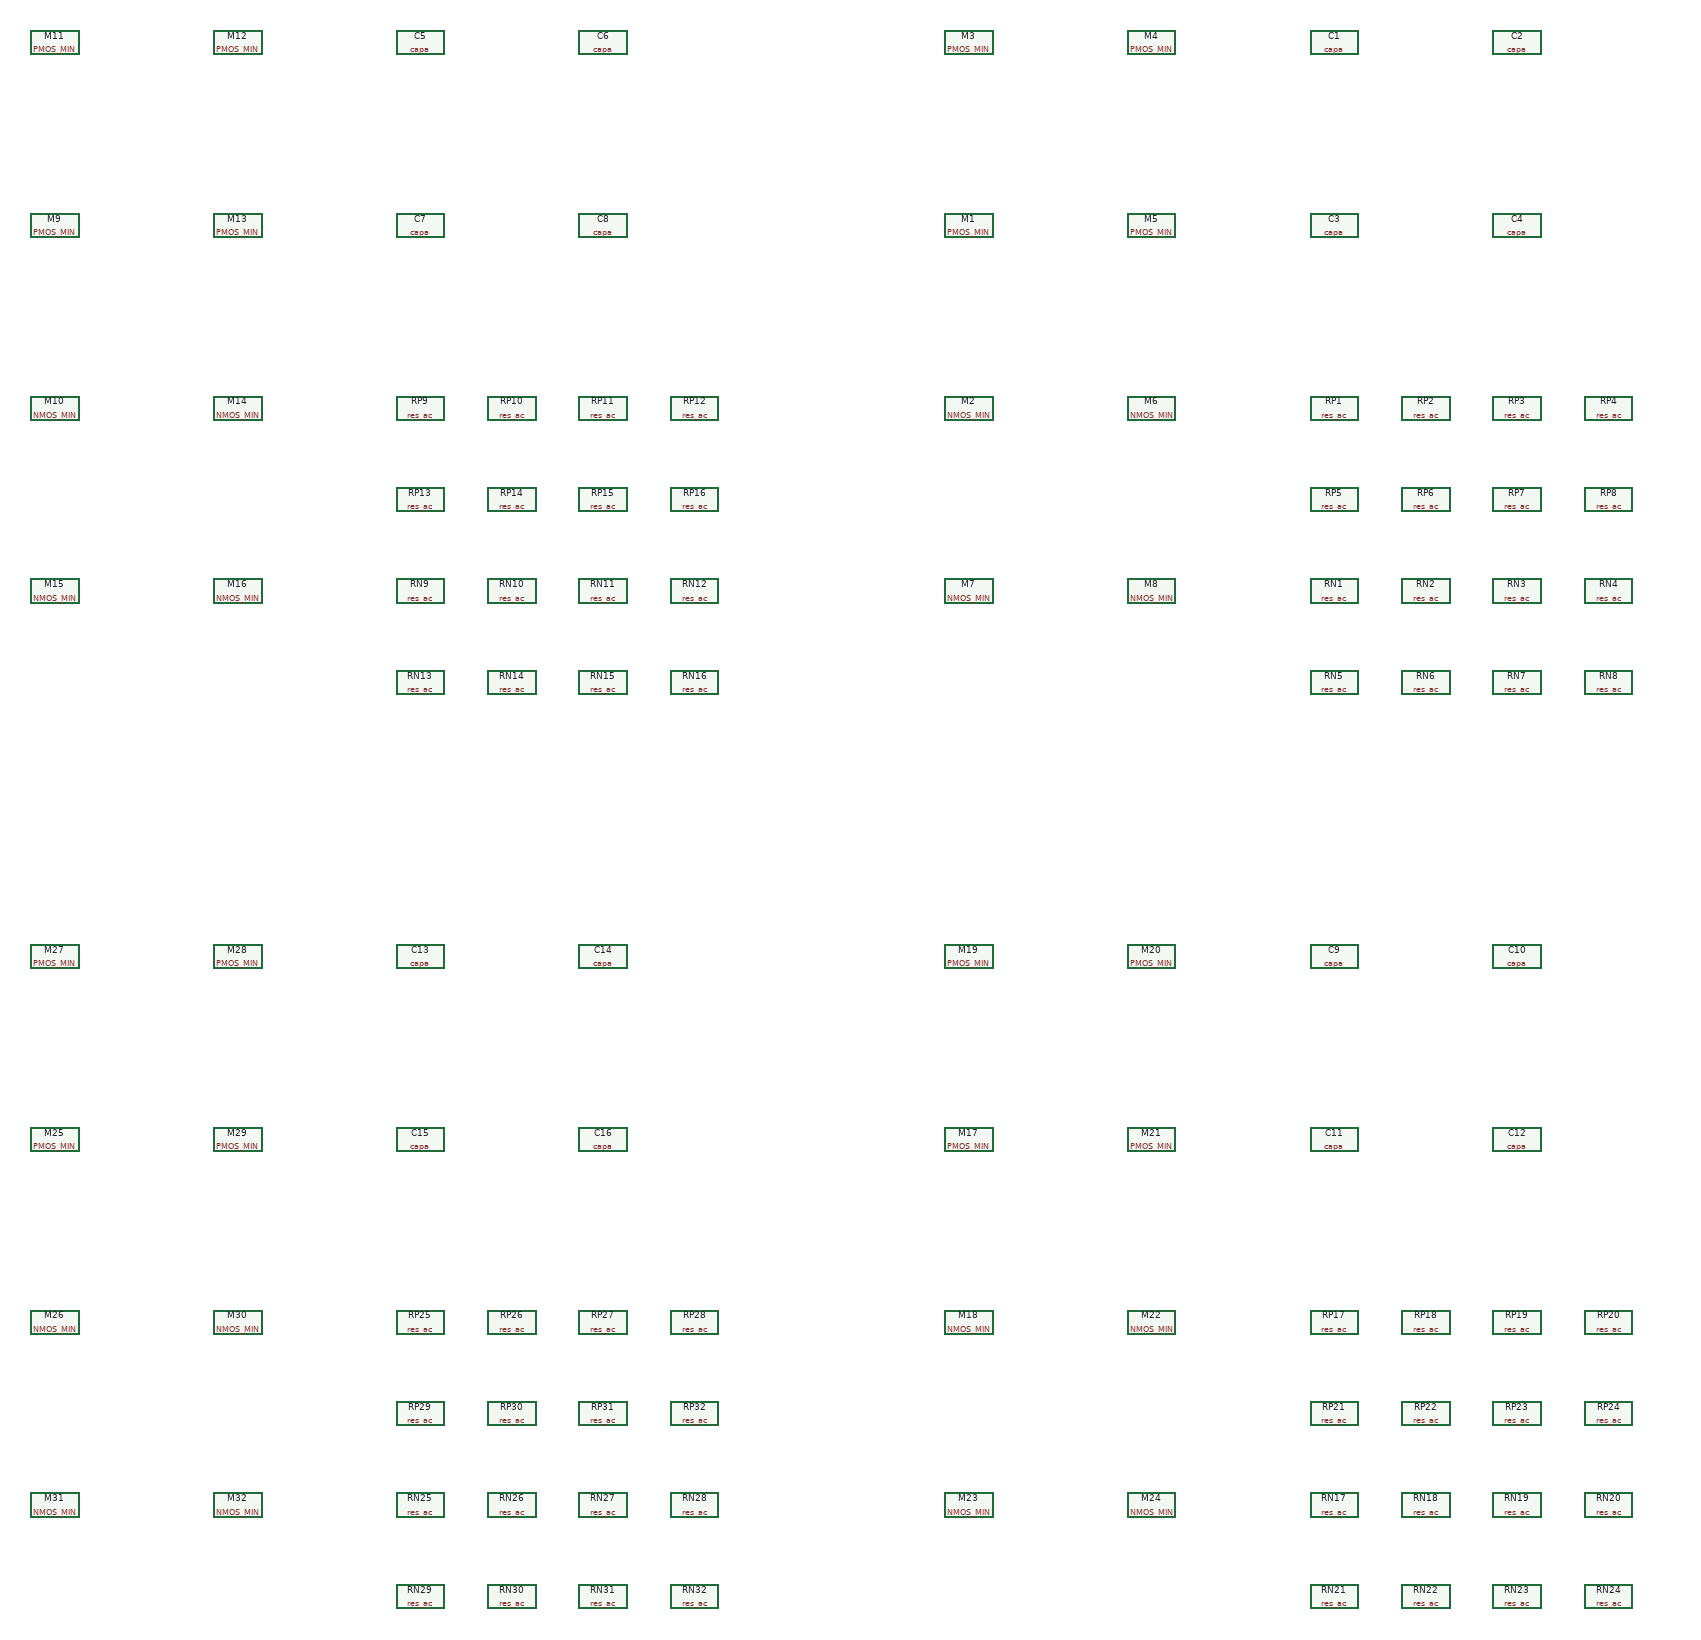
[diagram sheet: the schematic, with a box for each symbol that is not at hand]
v {xschem version=3.4.6RC file_version=1.2
}
G {}
K {}
V {}
S {}
E {}
C {PMOS_MIN.sym} 300 -900 0 0 {name=M1 model=pch w=40u l=10u as=0 ps=0 ad=0 pd=0 m=1}
C {NMOS_MIN.sym} 300 -600 0 0 {name=M2 model=nch w=10u l=10u as=0 ps=0 ad=0 pd=0 m=1}
C {PMOS_MIN.sym} 300 -1200 0 0 {name=M3 model=pch w=40u l=10u as=0 ps=0 ad=0 pd=0 m=1}
C {PMOS_MIN.sym} 600 -1200 0 0 {name=M4 model=pch w=40u l=10u as=0 ps=0 ad=0 pd=0 m=1}
C {PMOS_MIN.sym} 600 -900 0 0 {name=M5 model=pch w=40u l=10u as=0 ps=0 ad=0 pd=0 m=1}
C {NMOS_MIN.sym} 600 -600 0 0 {name=M6 model=nch w=10u l=10u as=0 ps=0 ad=0 pd=0 m=1}
C {NMOS_MIN.sym} 300 -300 0 0 {name=M7 model=nch w=10u l=10u as=0 ps=0 ad=0 pd=0 m=1}
C {NMOS_MIN.sym} 600 -300 0 0 {name=M8 model=nch w=10u l=10u as=0 ps=0 ad=0 pd=0 m=1}
C {devices/capa.sym} 900 -1200 0 0 {name=C1
m=1
value=0.413p
footprint=1206
device="ceramic capacitor"}
C {devices/capa.sym} 1200 -1200 0 0 {name=C2
m=1
value=0.413p
footprint=1206
device="ceramic capacitor"}
C {devices/capa.sym} 900 -900 0 0 {name=C3
m=1
value=0.413p
footprint=1206
device="ceramic capacitor"}
C {devices/capa.sym} 1200 -900 0 0 {name=C4
m=1
value=0.413p
footprint=1206
device="ceramic capacitor"}
C {devices/res_ac.sym} 900 -600 0 0 {name=RP1
value=3.6k
ac=1k
m=1}
C {devices/res_ac.sym} 1050 -600 0 0 {name=RP2
value=3.6k
ac=1k
m=1}
C {devices/res_ac.sym} 1200 -600 0 0 {name=RP3
value=3.6k
ac=1k
m=1}
C {devices/res_ac.sym} 1350 -600 0 0 {name=RP4
value=3.6k
ac=1k
m=1}
C {devices/res_ac.sym} 900 -450 0 0 {name=RP5
value=3.6k
ac=1k
m=1}
C {devices/res_ac.sym} 1050 -450 0 0 {name=RP6
value=3.6k
ac=1k
m=1}
C {devices/res_ac.sym} 1200 -450 0 0 {name=RP7
value=3.6k
ac=1k
m=1}
C {devices/res_ac.sym} 1350 -450 0 0 {name=RP8
value=3.6k
ac=1k
m=1}
C {devices/res_ac.sym} 900 -300 0 0 {name=RN1
value=0.54k
ac=1k
m=1}
C {devices/res_ac.sym} 1050 -300 0 0 {name=RN2
value=0.54k
ac=1k
m=1}
C {devices/res_ac.sym} 1200 -300 0 0 {name=RN3
value=0.54k
ac=1k
m=1}
C {devices/res_ac.sym} 1350 -300 0 0 {name=RN4
value=0.54k
ac=1k
m=1}
C {devices/res_ac.sym} 900 -150 0 0 {name=RN5
value=0.54k
ac=1k
m=1}
C {devices/res_ac.sym} 1050 -150 0 0 {name=RN6
value=0.54k
ac=1k
m=1}
C {devices/res_ac.sym} 1200 -150 0 0 {name=RN7
value=0.54k
ac=1k
m=1}
C {devices/res_ac.sym} 1350 -150 0 0 {name=RN8
value=0.54k
ac=1k
m=1}
C {PMOS_MIN.sym} -1200 -900 0 0 {name=M9 model=pch w=40u l=10u as=0 ps=0 ad=0 pd=0 m=1}
C {NMOS_MIN.sym} -1200 -600 0 0 {name=M10 model=nch w=10u l=10u as=0 ps=0 ad=0 pd=0 m=1}
C {PMOS_MIN.sym} -1200 -1200 0 0 {name=M11 model=pch w=40u l=10u as=0 ps=0 ad=0 pd=0 m=1}
C {PMOS_MIN.sym} -900 -1200 0 0 {name=M12 model=pch w=40u l=10u as=0 ps=0 ad=0 pd=0 m=1}
C {PMOS_MIN.sym} -900 -900 0 0 {name=M13 model=pch w=40u l=10u as=0 ps=0 ad=0 pd=0 m=1}
C {NMOS_MIN.sym} -900 -600 0 0 {name=M14 model=nch w=10u l=10u as=0 ps=0 ad=0 pd=0 m=1}
C {NMOS_MIN.sym} -1200 -300 0 0 {name=M15 model=nch w=10u l=10u as=0 ps=0 ad=0 pd=0 m=1}
C {NMOS_MIN.sym} -900 -300 0 0 {name=M16 model=nch w=10u l=10u as=0 ps=0 ad=0 pd=0 m=1}
C {devices/capa.sym} -600 -1200 0 0 {name=C5
m=1
value=0.413p
footprint=1206
device="ceramic capacitor"}
C {devices/capa.sym} -300 -1200 0 0 {name=C6
m=1
value=0.413p
footprint=1206
device="ceramic capacitor"}
C {devices/capa.sym} -600 -900 0 0 {name=C7
m=1
value=0.413p
footprint=1206
device="ceramic capacitor"}
C {devices/capa.sym} -300 -900 0 0 {name=C8
m=1
value=0.413p
footprint=1206
device="ceramic capacitor"}
C {devices/res_ac.sym} -600 -600 0 0 {name=RP9
value=3.6k
ac=1k
m=1}
C {devices/res_ac.sym} -450 -600 0 0 {name=RP10
value=3.6k
ac=1k
m=1}
C {devices/res_ac.sym} -300 -600 0 0 {name=RP11
value=3.6k
ac=1k
m=1}
C {devices/res_ac.sym} -150 -600 0 0 {name=RP12
value=3.6k
ac=1k
m=1}
C {devices/res_ac.sym} -600 -450 0 0 {name=RP13
value=3.6k
ac=1k
m=1}
C {devices/res_ac.sym} -450 -450 0 0 {name=RP14
value=3.6k
ac=1k
m=1}
C {devices/res_ac.sym} -300 -450 0 0 {name=RP15
value=3.6k
ac=1k
m=1}
C {devices/res_ac.sym} -150 -450 0 0 {name=RP16
value=3.6k
ac=1k
m=1}
C {devices/res_ac.sym} -600 -300 0 0 {name=RN9
value=0.54k
ac=1k
m=1}
C {devices/res_ac.sym} -450 -300 0 0 {name=RN10
value=0.54k
ac=1k
m=1}
C {devices/res_ac.sym} -300 -300 0 0 {name=RN11
value=0.54k
ac=1k
m=1}
C {devices/res_ac.sym} -150 -300 0 0 {name=RN12
value=0.54k
ac=1k
m=1}
C {devices/res_ac.sym} -600 -150 0 0 {name=RN13
value=0.54k
ac=1k
m=1}
C {devices/res_ac.sym} -450 -150 0 0 {name=RN14
value=0.54k
ac=1k
m=1}
C {devices/res_ac.sym} -300 -150 0 0 {name=RN15
value=0.54k
ac=1k
m=1}
C {devices/res_ac.sym} -150 -150 0 0 {name=RN16
value=0.54k
ac=1k
m=1}
C {PMOS_MIN.sym} 300 600 0 0 {name=M17 model=pch w=40u l=10u as=0 ps=0 ad=0 pd=0 m=1}
C {NMOS_MIN.sym} 300 900 0 0 {name=M18 model=nch w=10u l=10u as=0 ps=0 ad=0 pd=0 m=1}
C {PMOS_MIN.sym} 300 300 0 0 {name=M19 model=pch w=40u l=10u as=0 ps=0 ad=0 pd=0 m=1}
C {PMOS_MIN.sym} 600 300 0 0 {name=M20 model=pch w=40u l=10u as=0 ps=0 ad=0 pd=0 m=1}
C {PMOS_MIN.sym} 600 600 0 0 {name=M21 model=pch w=40u l=10u as=0 ps=0 ad=0 pd=0 m=1}
C {NMOS_MIN.sym} 600 900 0 0 {name=M22 model=nch w=10u l=10u as=0 ps=0 ad=0 pd=0 m=1}
C {NMOS_MIN.sym} 300 1200 0 0 {name=M23 model=nch w=10u l=10u as=0 ps=0 ad=0 pd=0 m=1}
C {NMOS_MIN.sym} 600 1200 0 0 {name=M24 model=nch w=10u l=10u as=0 ps=0 ad=0 pd=0 m=1}
C {devices/capa.sym} 900 300 0 0 {name=C9
m=1
value=0.413p
footprint=1206
device="ceramic capacitor"}
C {devices/capa.sym} 1200 300 0 0 {name=C10
m=1
value=0.413p
footprint=1206
device="ceramic capacitor"}
C {devices/capa.sym} 900 600 0 0 {name=C11
m=1
value=0.413p
footprint=1206
device="ceramic capacitor"}
C {devices/capa.sym} 1200 600 0 0 {name=C12
m=1
value=0.413p
footprint=1206
device="ceramic capacitor"}
C {devices/res_ac.sym} 900 900 0 0 {name=RP17
value=3.6k
ac=1k
m=1}
C {devices/res_ac.sym} 1050 900 0 0 {name=RP18
value=3.6k
ac=1k
m=1}
C {devices/res_ac.sym} 1200 900 0 0 {name=RP19
value=3.6k
ac=1k
m=1}
C {devices/res_ac.sym} 1350 900 0 0 {name=RP20
value=3.6k
ac=1k
m=1}
C {devices/res_ac.sym} 900 1050 0 0 {name=RP21
value=3.6k
ac=1k
m=1}
C {devices/res_ac.sym} 1050 1050 0 0 {name=RP22
value=3.6k
ac=1k
m=1}
C {devices/res_ac.sym} 1200 1050 0 0 {name=RP23
value=3.6k
ac=1k
m=1}
C {devices/res_ac.sym} 1350 1050 0 0 {name=RP24
value=3.6k
ac=1k
m=1}
C {devices/res_ac.sym} 900 1200 0 0 {name=RN17
value=0.54k
ac=1k
m=1}
C {devices/res_ac.sym} 1050 1200 0 0 {name=RN18
value=0.54k
ac=1k
m=1}
C {devices/res_ac.sym} 1200 1200 0 0 {name=RN19
value=0.54k
ac=1k
m=1}
C {devices/res_ac.sym} 1350 1200 0 0 {name=RN20
value=0.54k
ac=1k
m=1}
C {devices/res_ac.sym} 900 1350 0 0 {name=RN21
value=0.54k
ac=1k
m=1}
C {devices/res_ac.sym} 1050 1350 0 0 {name=RN22
value=0.54k
ac=1k
m=1}
C {devices/res_ac.sym} 1200 1350 0 0 {name=RN23
value=0.54k
ac=1k
m=1}
C {devices/res_ac.sym} 1350 1350 0 0 {name=RN24
value=0.54k
ac=1k
m=1}
C {PMOS_MIN.sym} -1200 600 0 0 {name=M25 model=pch w=40u l=10u as=0 ps=0 ad=0 pd=0 m=1}
C {NMOS_MIN.sym} -1200 900 0 0 {name=M26 model=nch w=10u l=10u as=0 ps=0 ad=0 pd=0 m=1}
C {PMOS_MIN.sym} -1200 300 0 0 {name=M27 model=pch w=40u l=10u as=0 ps=0 ad=0 pd=0 m=1}
C {PMOS_MIN.sym} -900 300 0 0 {name=M28 model=pch w=40u l=10u as=0 ps=0 ad=0 pd=0 m=1}
C {PMOS_MIN.sym} -900 600 0 0 {name=M29 model=pch w=40u l=10u as=0 ps=0 ad=0 pd=0 m=1}
C {NMOS_MIN.sym} -900 900 0 0 {name=M30 model=nch w=10u l=10u as=0 ps=0 ad=0 pd=0 m=1}
C {NMOS_MIN.sym} -1200 1200 0 0 {name=M31 model=nch w=10u l=10u as=0 ps=0 ad=0 pd=0 m=1}
C {NMOS_MIN.sym} -900 1200 0 0 {name=M32 model=nch w=10u l=10u as=0 ps=0 ad=0 pd=0 m=1}
C {devices/capa.sym} -600 300 0 0 {name=C13
m=1
value=0.413p
footprint=1206
device="ceramic capacitor"}
C {devices/capa.sym} -300 300 0 0 {name=C14
m=1
value=0.413p
footprint=1206
device="ceramic capacitor"}
C {devices/capa.sym} -600 600 0 0 {name=C15
m=1
value=0.413p
footprint=1206
device="ceramic capacitor"}
C {devices/capa.sym} -300 600 0 0 {name=C16
m=1
value=0.413p
footprint=1206
device="ceramic capacitor"}
C {devices/res_ac.sym} -600 900 0 0 {name=RP25
value=3.6k
ac=1k
m=1}
C {devices/res_ac.sym} -450 900 0 0 {name=RP26
value=3.6k
ac=1k
m=1}
C {devices/res_ac.sym} -300 900 0 0 {name=RP27
value=3.6k
ac=1k
m=1}
C {devices/res_ac.sym} -150 900 0 0 {name=RP28
value=3.6k
ac=1k
m=1}
C {devices/res_ac.sym} -600 1050 0 0 {name=RP29
value=3.6k
ac=1k
m=1}
C {devices/res_ac.sym} -450 1050 0 0 {name=RP30
value=3.6k
ac=1k
m=1}
C {devices/res_ac.sym} -300 1050 0 0 {name=RP31
value=3.6k
ac=1k
m=1}
C {devices/res_ac.sym} -150 1050 0 0 {name=RP32
value=3.6k
ac=1k
m=1}
C {devices/res_ac.sym} -600 1200 0 0 {name=RN25
value=0.54k
ac=1k
m=1}
C {devices/res_ac.sym} -450 1200 0 0 {name=RN26
value=0.54k
ac=1k
m=1}
C {devices/res_ac.sym} -300 1200 0 0 {name=RN27
value=0.54k
ac=1k
m=1}
C {devices/res_ac.sym} -150 1200 0 0 {name=RN28
value=0.54k
ac=1k
m=1}
C {devices/res_ac.sym} -600 1350 0 0 {name=RN29
value=0.54k
ac=1k
m=1}
C {devices/res_ac.sym} -450 1350 0 0 {name=RN30
value=0.54k
ac=1k
m=1}
C {devices/res_ac.sym} -300 1350 0 0 {name=RN31
value=0.54k
ac=1k
m=1}
C {devices/res_ac.sym} -150 1350 0 0 {name=RN32
value=0.54k
ac=1k
m=1}
